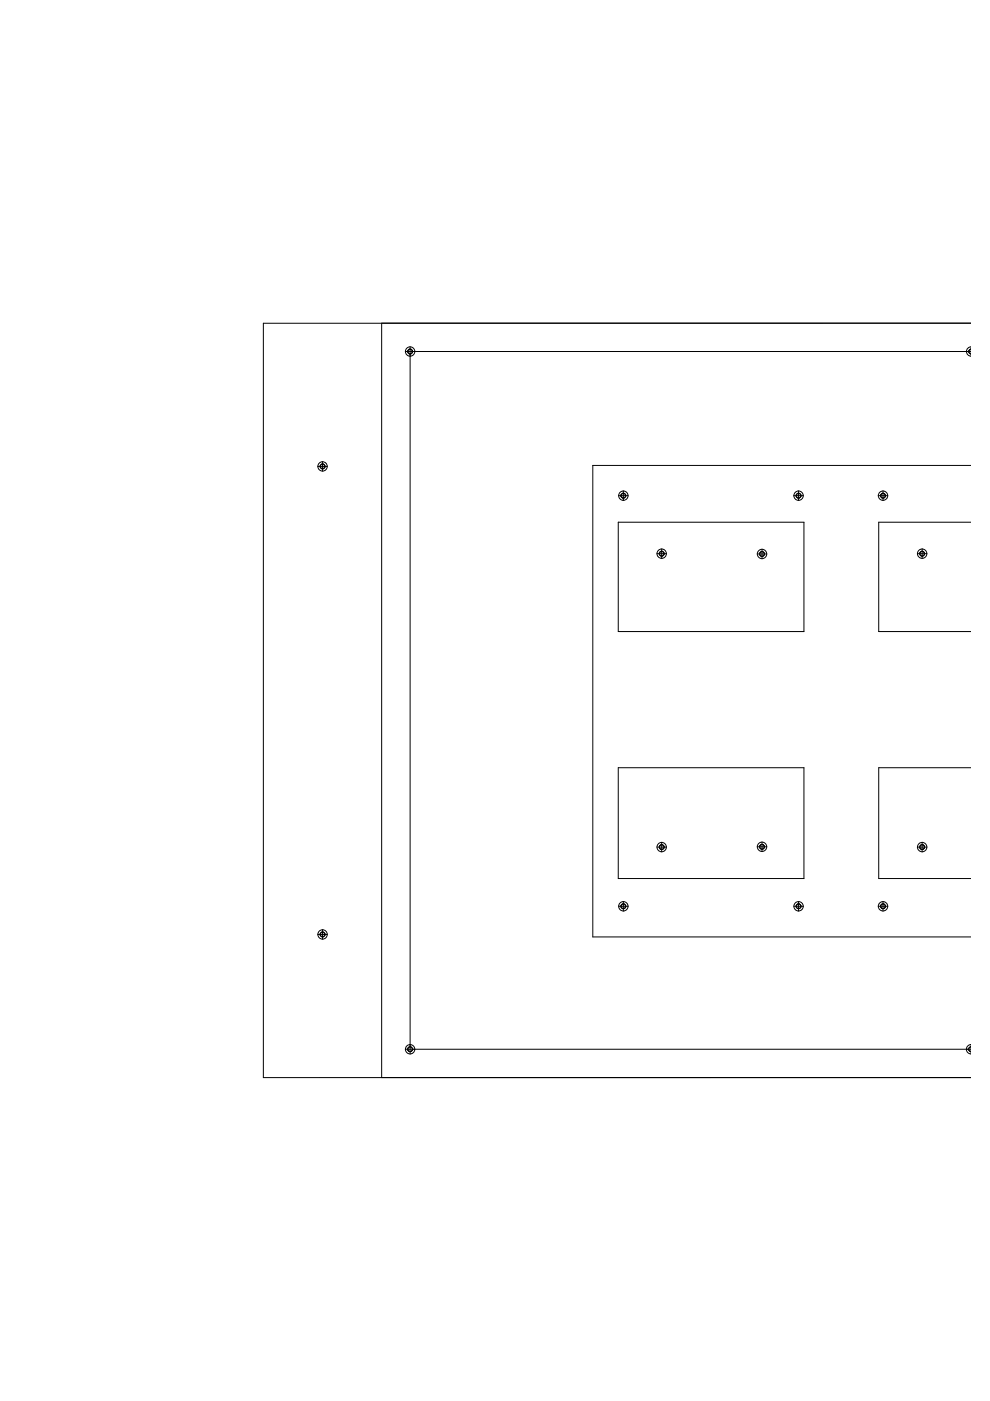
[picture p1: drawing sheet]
<svg xmlns="http://www.w3.org/2000/svg" width="210mm" height="297mm" viewBox="0 0 210 297" stroke-linecap="round" stroke-linejoin="round" font-family="sans-serif">
<g fill="none" stroke="#000" stroke-width=".21">
<path d="M205.8 68.5h-124.9v160h124.9M205.8 74.5h-118.8v148h118.8M205.8 98.7h-80.1v99.9h80.1M131.1 110.7h39.4v23.2h-39.4zM205.8 110.7h-19.5v23.2h19.5M131.1 162.8h39.4v23.5h-39.4zM205.8 162.8h-19.5v23.5h19.5"/>
<circle cx="132.2" cy="105.1" r=".51"/>
</g>
<circle cx="132.2" cy="105.1" r=".51" fill="#fff" stroke="#000" stroke-width=".21"/>
<circle cx="169.3" cy="105.1" r=".51" fill="none" stroke="#000" stroke-width=".21"/>
<circle cx="169.3" cy="105.1" r=".51" fill="#fff" stroke="#000" stroke-width=".21"/>
<circle cx="132.2" cy="192.2" r=".51" fill="none" stroke="#000" stroke-width=".21"/>
<circle cx="132.2" cy="192.2" r=".51" fill="#fff" stroke="#000" stroke-width=".21"/>
<circle cx="169.3" cy="192.2" r=".51" fill="none" stroke="#000" stroke-width=".21"/>
<circle cx="169.3" cy="192.2" r=".51" fill="#fff" stroke="#000" stroke-width=".21"/>
<circle cx="187.2" cy="105.1" r=".51" fill="none" stroke="#000" stroke-width=".21"/>
<circle cx="187.2" cy="105.1" r=".51" fill="#fff" stroke="#000" stroke-width=".21"/>
<circle cx="187.2" cy="192.2" r=".51" fill="none" stroke="#000" stroke-width=".21"/>
<circle cx="187.2" cy="192.2" r=".51" fill="#fff" stroke="#000" stroke-width=".21"/>
<g fill="none" stroke="#000" stroke-width=".21">
<path d="M205.8 68.5h-150v160h150"/>
<circle cx="87" cy="74.5" r=".51"/>
</g>
<circle cx="87" cy="74.5" r=".51" fill="#fff" stroke="#000" stroke-width=".21"/>
<path d="M205.8 74.1a.48 .48 0 0 0-.4 .4 .48 .48 0 0 0 .4 .5" fill="none" stroke="#000" stroke-width=".21"/>
<path d="M205.5 74.3l.3-.3v1a.54 .54 0 0 1-.3-.7z" fill-rule="evenodd" fill="#fff" stroke="#000" stroke-width=".21"/>
<path d="M205.8 222a.49 .49 0 0 0-.4 .5 .49 .49 0 0 0 .4 .4" fill="none" stroke="#000" stroke-width=".21"/>
<path d="M205.4 222.2l.4-.2v1a.53 .53 0 0 1-.4-.8z" fill-rule="evenodd" fill="#fff" stroke="#000" stroke-width=".21"/>
<circle cx="87" cy="222.5" r=".51" fill="none" stroke="#000" stroke-width=".21"/>
<circle cx="87" cy="222.5" r=".51" fill="#fff" stroke="#000" stroke-width=".21"/>
<circle cx="140.3" cy="117.4" r=".51" fill="none" stroke="#000" stroke-width=".21"/>
<circle cx="140.3" cy="117.4" r=".51" fill="#fff" stroke="#000" stroke-width=".21"/>
<circle cx="161.6" cy="117.5" r=".51" fill="none" stroke="#000" stroke-width=".21"/>
<circle cx="161.6" cy="117.5" r=".51" fill="#fff" stroke="#000" stroke-width=".21"/>
<circle cx="195.5" cy="117.4" r=".51" fill="none" stroke="#000" stroke-width=".21"/>
<circle cx="195.5" cy="117.4" r=".51" fill="#fff" stroke="#000" stroke-width=".21"/>
<circle cx="195.5" cy="179.6" r=".51" fill="none" stroke="#000" stroke-width=".21"/>
<circle cx="195.5" cy="179.6" r=".51" fill="#fff" stroke="#000" stroke-width=".21"/>
<circle cx="161.6" cy="179.5" r=".51" fill="none" stroke="#000" stroke-width=".21"/>
<circle cx="161.6" cy="179.5" r=".51" fill="#fff" stroke="#000" stroke-width=".21"/>
<circle cx="140.3" cy="179.6" r=".51" fill="none" stroke="#000" stroke-width=".21"/>
<circle cx="140.3" cy="179.6" r=".51" fill="#fff" stroke="#000" stroke-width=".21"/>
<circle cx="68.4" cy="98.9" r=".51" fill="none" stroke="#000" stroke-width=".21"/>
<circle cx="68.4" cy="98.9" r=".51" fill="#fff" stroke="#000" stroke-width=".21"/>
<circle cx="68.4" cy="198.1" r=".51" fill="none" stroke="#000" stroke-width=".21"/>
<circle cx="68.4" cy="198.1" r=".51" fill="#fff" stroke="#000" stroke-width=".21"/>
<g fill="none" stroke="#000" stroke-width=".21">
<path d="M85.9 74.5h2.1M87 73.5v2M204.9 74.5h.9M205.8 73.6a.97 .97 0 0 0-.9 .9 .97 .97 0 0 0 .9 1M205.8 74.1a.46 .46 0 0 0-.4 .4 .46 .46 0 0 0 .4 .5M67.4 98.9h2M68.4 97.9v2M131.1 105.1h2.1M132.2 104.1v2M139.3 117.4h2M140.3 116.4v2M160.5 117.5h2.1"/>
<path d="M161.6 116.4v2.1M168.3 105.1h2M169.3 104.1v2M186.2 105.1h2M187.2 104.1v2M194.5 117.4h2M195.5 116.4v2M139.3 179.6h2M140.3 178.6v2M160.5 179.5h2.1M161.6 178.5v2.1M194.5 179.6h2"/>
<path d="M195.5 178.6v2M67.4 198.1h2M68.4 197.1v2M131.1 192.2h2.1M132.2 191.1v2.1M168.3 192.2h2M169.3 191.1v2.1M186.2 192.2h2M187.2 191.1v2.1M85.9 222.5h2.1M87 221.4v2.1M204.9 222.5h.9"/>
<path d="M205.8 221.5a.98 .98 0 0 0-.9 1 .98 .98 0 0 0 .9 .9M205.8 222a.46 .46 0 0 0-.4 .5 .46 .46 0 0 0 .4 .4"/>
<circle cx="87" cy="74.5" r=".99"/>
<circle cx="87" cy="74.5" r=".49"/>
<circle cx="68.4" cy="98.9" r=".99"/>
<circle cx="68.4" cy="98.9" r=".49"/>
<circle cx="132.2" cy="105.1" r=".99"/>
<circle cx="132.2" cy="105.1" r=".49"/>
<circle cx="140.3" cy="117.4" r=".99"/>
<circle cx="140.3" cy="117.4" r=".49"/>
<circle cx="161.6" cy="117.5" r=".99"/>
<circle cx="161.6" cy="117.5" r=".49"/>
<circle cx="169.3" cy="105.1" r=".99"/>
<circle cx="169.3" cy="105.1" r=".49"/>
<circle cx="187.2" cy="105.1" r=".99"/>
<circle cx="187.2" cy="105.1" r=".49"/>
<circle cx="195.5" cy="117.4" r=".99"/>
<circle cx="195.5" cy="117.4" r=".49"/>
<circle cx="140.3" cy="179.6" r=".99"/>
<circle cx="140.3" cy="179.6" r=".49"/>
<circle cx="161.6" cy="179.5" r=".99"/>
<circle cx="161.6" cy="179.5" r=".49"/>
<circle cx="195.5" cy="179.6" r=".99"/>
<circle cx="195.5" cy="179.6" r=".49"/>
<circle cx="68.4" cy="198.1" r=".99"/>
<circle cx="68.4" cy="198.1" r=".49"/>
<circle cx="132.2" cy="192.2" r=".99"/>
<circle cx="132.2" cy="192.2" r=".49"/>
<circle cx="169.3" cy="192.2" r=".99"/>
<circle cx="169.3" cy="192.2" r=".49"/>
<circle cx="187.2" cy="192.2" r=".99"/>
<circle cx="187.2" cy="192.2" r=".49"/>
<circle cx="87" cy="222.5" r=".99"/>
<circle cx="87" cy="222.5" r=".49"/>
</g>
</svg>
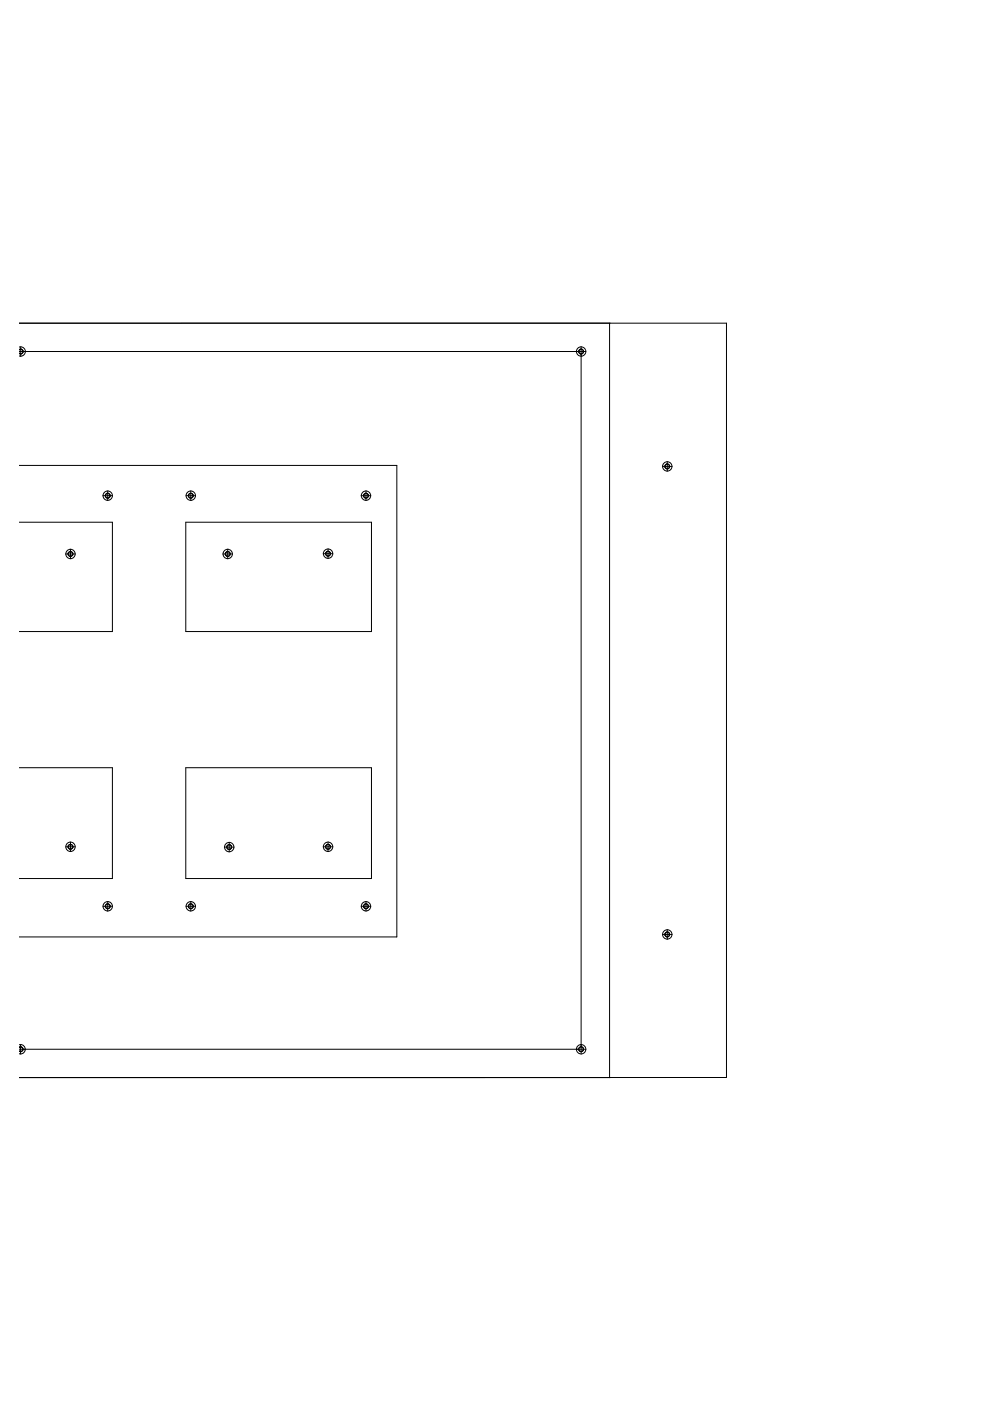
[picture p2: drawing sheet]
<svg xmlns="http://www.w3.org/2000/svg" width="210mm" height="297mm" viewBox="0 0 210 297" stroke-linecap="round" stroke-linejoin="round" font-family="sans-serif">
<g fill="none" stroke="#000" stroke-width=".21">
<path d="M4.1 74.5h119.1v148h-119.1M4.1 68.5h125.3M129.2 68.5v160M4.1 98.7h80v99.9h-80M4.1 110.7h19.7v23.2h-19.7M39.4 110.7h39.4v23.2h-39.4zM4.1 162.8h19.7v23.5h-19.7M39.4 162.8h39.4v23.5h-39.4zM4.1 228.5h125.3"/>
<circle cx="40.4" cy="105.1" r=".51"/>
</g>
<circle cx="40.4" cy="105.1" r=".51" fill="#fff" stroke="#000" stroke-width=".21"/>
<circle cx="77.6" cy="105.1" r=".51" fill="none" stroke="#000" stroke-width=".21"/>
<circle cx="77.6" cy="105.1" r=".51" fill="#fff" stroke="#000" stroke-width=".21"/>
<circle cx="40.4" cy="192.2" r=".51" fill="none" stroke="#000" stroke-width=".21"/>
<circle cx="40.4" cy="192.2" r=".51" fill="#fff" stroke="#000" stroke-width=".21"/>
<circle cx="77.6" cy="192.2" r=".51" fill="none" stroke="#000" stroke-width=".21"/>
<circle cx="77.6" cy="192.2" r=".51" fill="#fff" stroke="#000" stroke-width=".21"/>
<circle cx="22.8" cy="105.1" r=".51" fill="none" stroke="#000" stroke-width=".21"/>
<circle cx="22.8" cy="105.1" r=".51" fill="#fff" stroke="#000" stroke-width=".21"/>
<circle cx="22.8" cy="192.2" r=".51" fill="none" stroke="#000" stroke-width=".21"/>
<circle cx="22.8" cy="192.2" r=".51" fill="#fff" stroke="#000" stroke-width=".21"/>
<path d="M4.1 68.5h149.9v160h-149.9M4.1 74.1a.51 .51 0 0 1 .8 .4 .51 .51 0 0 1-.8 .5" fill="none" stroke="#000" stroke-width=".21"/>
<path d="M4.1 74.1a.5 .5 0 0 1 .8 .4 .5 .5 0 0 1-.8 .5z" fill-rule="evenodd" fill="#fff" stroke="#000" stroke-width=".21"/>
<circle cx="123.2" cy="74.5" r=".51" fill="none" stroke="#000" stroke-width=".21"/>
<circle cx="123.2" cy="74.5" r=".51" fill="#fff" stroke="#000" stroke-width=".21"/>
<circle cx="123.2" cy="222.5" r=".51" fill="none" stroke="#000" stroke-width=".21"/>
<circle cx="123.2" cy="222.5" r=".51" fill="#fff" stroke="#000" stroke-width=".21"/>
<path d="M4.1 222a.5 .5 0 0 1 .8 .5 .5 .5 0 0 1-.8 .4" fill="none" stroke="#000" stroke-width=".21"/>
<path d="M4.1 222a.5 .5 0 0 1 .8 .5 .5 .5 0 0 1-.8 .4z" fill-rule="evenodd" fill="#fff" stroke="#000" stroke-width=".21"/>
<circle cx="14.9" cy="117.5" r=".51" fill="none" stroke="#000" stroke-width=".21"/>
<circle cx="14.9" cy="117.5" r=".51" fill="#fff" stroke="#000" stroke-width=".21"/>
<circle cx="48.3" cy="117.5" r=".51" fill="none" stroke="#000" stroke-width=".21"/>
<circle cx="48.3" cy="117.5" r=".51" fill="#fff" stroke="#000" stroke-width=".21"/>
<circle cx="69.6" cy="117.4" r=".51" fill="none" stroke="#000" stroke-width=".21"/>
<circle cx="69.6" cy="117.4" r=".51" fill="#fff" stroke="#000" stroke-width=".21"/>
<circle cx="69.6" cy="179.5" r=".51" fill="none" stroke="#000" stroke-width=".21"/>
<circle cx="69.6" cy="179.5" r=".51" fill="#fff" stroke="#000" stroke-width=".21"/>
<circle cx="48.6" cy="179.6" r=".51" fill="none" stroke="#000" stroke-width=".21"/>
<circle cx="48.6" cy="179.6" r=".51" fill="#fff" stroke="#000" stroke-width=".21"/>
<circle cx="14.9" cy="179.5" r=".51" fill="none" stroke="#000" stroke-width=".21"/>
<circle cx="14.9" cy="179.5" r=".51" fill="#fff" stroke="#000" stroke-width=".21"/>
<circle cx="141.5" cy="198.1" r=".51" fill="none" stroke="#000" stroke-width=".21"/>
<circle cx="141.5" cy="198.1" r=".51" fill="#fff" stroke="#000" stroke-width=".21"/>
<circle cx="141.5" cy="98.9" r=".51" fill="none" stroke="#000" stroke-width=".21"/>
<circle cx="141.5" cy="98.9" r=".51" fill="#fff" stroke="#000" stroke-width=".21"/>
<g fill="none" stroke="#000" stroke-width=".21">
<path d="M4.1 73.6a.98 .98 0 0 1 1.3 .9 .98 .98 0 0 1-1.3 1M4.1 74.1a.49 .49 0 0 1 .8 .4 .49 .49 0 0 1-.8 .4M4.1 74.5h1.3M4.4 73.5v2M122.2 74.5h2M123.2 73.5v2M140.5 98.9h2M141.5 97.9v2M13.9 117.5h2.1M14.9 116.4v2.1M21.8 105.1h2.1M22.8 104.1v2"/>
<path d="M39.4 105.1h2.1M40.4 104.1v2M47.3 117.5h2M48.3 116.4v2.1M68.5 117.4h2.1M69.6 116.4v2M76.6 105.1h2M77.6 104.1v2M13.9 179.5h2.1M14.9 178.5v2.1M47.6 179.6h2M48.6 178.6v2"/>
<path d="M68.5 179.5h2.1M69.6 178.5v2.1M21.8 192.2h2.1M22.8 191.1v2.1M39.4 192.2h2.1M40.4 191.1v2.1M76.6 192.2h2M77.6 191.1v2.1M140.5 198.1h2M141.5 197.1v2M4.1 221.5a.96 .96 0 0 1 1.3 1M4.1 222a.48 .48 0 0 1 .7 .5 .48 .48 0 0 1-.7 .4"/>
<path d="M4.1 222.5h1.3M4.4 221.4v2.1M5.4 222.5a.97 .97 0 0 1-1.3 .9M122.2 222.5h2M123.2 221.4v2.1"/>
<circle cx="123.2" cy="74.5" r=".99"/>
<circle cx="123.2" cy="74.5" r=".49"/>
<circle cx="141.5" cy="98.9" r=".99"/>
<circle cx="141.5" cy="98.9" r=".49"/>
<circle cx="14.9" cy="117.5" r=".99"/>
<circle cx="14.9" cy="117.5" r=".49"/>
<circle cx="22.8" cy="105.1" r=".99"/>
<circle cx="22.8" cy="105.1" r=".49"/>
<circle cx="40.4" cy="105.1" r=".99"/>
<circle cx="40.4" cy="105.1" r=".49"/>
<circle cx="48.3" cy="117.5" r=".99"/>
<circle cx="48.3" cy="117.5" r=".49"/>
<circle cx="69.6" cy="117.4" r=".99"/>
<circle cx="69.6" cy="117.4" r=".49"/>
<circle cx="77.6" cy="105.1" r=".99"/>
<circle cx="77.6" cy="105.1" r=".49"/>
<circle cx="14.9" cy="179.5" r=".99"/>
<circle cx="14.9" cy="179.5" r=".49"/>
<circle cx="48.6" cy="179.6" r=".99"/>
<circle cx="48.6" cy="179.6" r=".49"/>
<circle cx="69.6" cy="179.5" r=".99"/>
<circle cx="69.6" cy="179.5" r=".49"/>
<circle cx="22.8" cy="192.2" r=".99"/>
<circle cx="22.8" cy="192.2" r=".49"/>
<circle cx="40.4" cy="192.2" r=".99"/>
<circle cx="40.4" cy="192.2" r=".49"/>
<circle cx="77.6" cy="192.2" r=".99"/>
<circle cx="77.6" cy="192.2" r=".49"/>
<circle cx="141.5" cy="198.1" r=".99"/>
<circle cx="141.5" cy="198.1" r=".49"/>
<circle cx="123.2" cy="222.5" r=".99"/>
<circle cx="123.2" cy="222.5" r=".49"/>
</g>
</svg>
